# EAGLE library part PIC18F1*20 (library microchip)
18/20/28-Pin High-Performance, Enhanced Flash Microcontrollers with 10-bit A/D and nanoWatt Technology Source: ww1.microchip.com/downloads/en/DeviceDoc/39605c.pdf

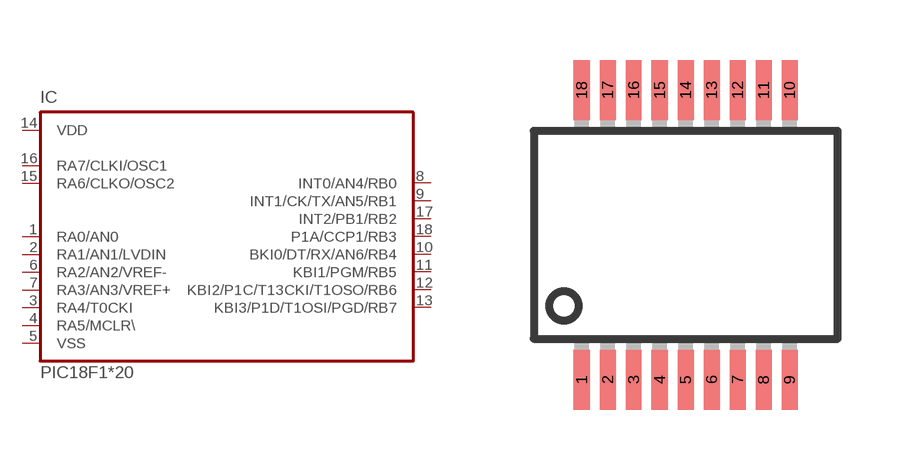
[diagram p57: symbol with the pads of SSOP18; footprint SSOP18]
Designator prefix IC

## PIC18F1220SO, PIC18F1320SO  [SSOP18]
1  RA0/AN0
2  RA1/AN1/LVDIN
3  RA4/T0CKI
4  RA5/MCLR\  in
5  VSS  pwr
6  RA2/AN2/VREF-
7  RA3/AN3/VREF+
8  INT0/AN4/RB0
9  INT1/CK/TX/AN5/RB1
10  BKI0/DT/RX/AN6/RB4
11  KBI1/PGM/RB5
12  KBI2/P1C/T13CKI/T1OSO/RB6
13  KBI3/P1D/T1OSI/PGD/RB7
14  VDD  pwr
15  RA6/CLKO/OSC2
16  RA7/CLKI/OSC1
17  INT2/PB1/RB2
18  P1A/CCP1/RB3

## Footprint SSOP18 (pad centres in mm)
Shrink Small Outline Package package type SS Source: ww1.microchip.com/downloads/en/DeviceDoc/39605c.pdf
smd 0.4 x 1.5: 1 -2.6,-3.625; 2 -1.95,-3.625; 3 -1.3,-3.625; 4 -0.65,-3.625; 5 0,-3.625; 6 0.65,-3.625; 7 1.3,-3.625; 8 1.95,-3.625; 9 2.6,-3.625; 10 2.6,3.625; 11 1.95,3.625; 12 1.3,3.625; 13 0.65,3.625; 14 0,3.625; 15 -0.65,3.625; 16 -1.3,3.625; 17 -1.95,3.625; 18 -2.6,3.625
